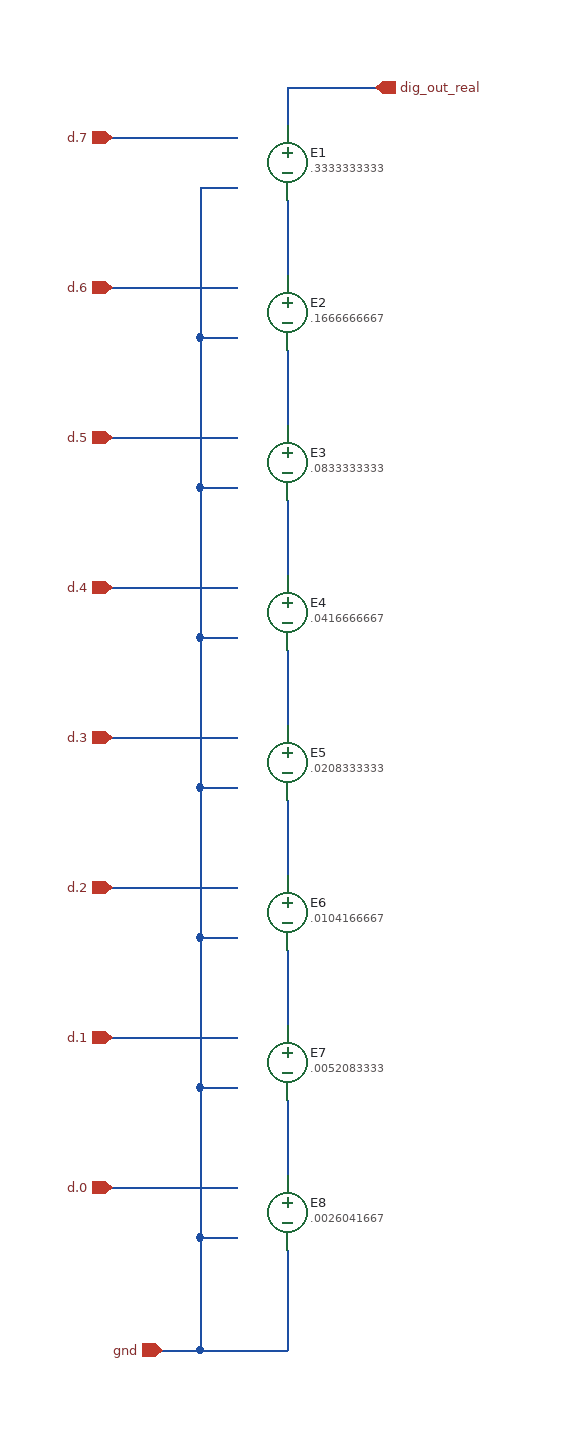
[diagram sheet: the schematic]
v {xschem version=3.4.6RC file_version=1.2
}
G {}
K {}
V {}
S {}
E {}
N 490 -1100 490 -1070 {lab=dig_out_real}
N 490 -1100 560 -1100 {lab=dig_out_real}
N 490 -1010 490 -980 {lab=#net1}
N 380 -1060 450 -1060 {lab=d.0}
N 420 -1020 450 -1020 {lab=gnd}
N 420 -1020 420 -990 {lab=gnd}
N 350 -1060 380 -1060 {lab=d.0}
N 490 -980 490 -950 {lab=#net1}
N 490 -890 490 -860 {lab=#net2}
N 380 -940 450 -940 {lab=d.6}
N 420 -900 450 -900 {lab=gnd}
N 420 -900 420 -870 {lab=gnd}
N 350 -940 380 -940 {lab=d.6}
N 490 -860 490 -830 {lab=#net2}
N 490 -770 490 -740 {lab=#net3}
N 380 -820 450 -820 {lab=d.5}
N 420 -780 450 -780 {lab=gnd}
N 420 -780 420 -750 {lab=gnd}
N 350 -820 380 -820 {lab=d.5}
N 490 -740 490 -710 {lab=#net3}
N 490 -650 490 -620 {lab=#net4}
N 380 -700 450 -700 {lab=d.4}
N 420 -660 450 -660 {lab=gnd}
N 420 -660 420 -630 {lab=gnd}
N 350 -700 380 -700 {lab=d.4}
N 490 -620 490 -590 {lab=#net4}
N 490 -530 490 -500 {lab=#net5}
N 380 -580 450 -580 {lab=d.3}
N 420 -540 450 -540 {lab=gnd}
N 420 -540 420 -510 {lab=gnd}
N 350 -580 380 -580 {lab=d.3}
N 490 -500 490 -470 {lab=#net5}
N 490 -410 490 -380 {lab=#net6}
N 380 -460 450 -460 {lab=d.2}
N 420 -420 450 -420 {lab=gnd}
N 420 -420 420 -390 {lab=gnd}
N 350 -460 380 -460 {lab=d.2}
N 490 -380 490 -350 {lab=#net6}
N 490 -290 490 -260 {lab=#net7}
N 380 -340 450 -340 {lab=d.1}
N 420 -300 450 -300 {lab=gnd}
N 420 -300 420 -270 {lab=gnd}
N 350 -340 380 -340 {lab=d.1}
N 490 -260 490 -230 {lab=#net7}
N 490 -170 490 -140 {lab=gnd}
N 380 -220 450 -220 {lab=d.0}
N 420 -180 450 -180 {lab=gnd}
N 420 -180 420 -150 {lab=gnd}
N 350 -220 380 -220 {lab=d.0}
N 490 -140 490 -120 {lab=gnd}
N 420 -150 420 -90 {lab=gnd}
N 390 -90 420 -90 {lab=gnd}
N 420 -90 490 -90 {lab=gnd}
N 490 -120 490 -90 {lab=gnd}
N 420 -270 420 -180 {lab=gnd}
N 420 -390 420 -300 {lab=gnd}
N 420 -510 420 -420 {lab=gnd}
N 420 -630 420 -540 {lab=gnd}
N 420 -750 420 -660 {lab=gnd}
N 420 -870 420 -780 {lab=gnd}
N 420 -990 420 -900 {lab=gnd}
C {vcvs.sym} 490 -1040 0 0 {name=E1 value=.3333333333}
C {vcvs.sym} 490 -920 0 0 {name=E2 value=.1666666667}
C {vcvs.sym} 490 -800 0 0 {name=E3 value=.0833333333}
C {vcvs.sym} 490 -680 0 0 {name=E4 value=.0416666667}
C {vcvs.sym} 490 -560 0 0 {name=E5 value=.0208333333}
C {vcvs.sym} 490 -440 0 0 {name=E6 value=.0104166667}
C {vcvs.sym} 490 -320 0 0 {name=E7 value=.0052083333}
C {vcvs.sym} 490 -200 0 0 {name=E8 value=.0026041667}
C {iopin.sym} 390 -90 2 0 {name=p1 lab=gnd}
C {ipin.sym} 350 -220 0 0 {name=p12 lab=d.0}
C {ipin.sym} 350 -340 0 0 {name=p2 lab=d.1}
C {ipin.sym} 350 -460 0 0 {name=p3 lab=d.2}
C {ipin.sym} 350 -580 0 0 {name=p4 lab=d.3}
C {ipin.sym} 350 -700 0 0 {name=p5 lab=d.4}
C {ipin.sym} 350 -820 0 0 {name=p6 lab=d.5}
C {ipin.sym} 350 -940 0 0 {name=p7 lab=d.6}
C {ipin.sym} 350 -1060 0 0 {name=p8 lab=d.7}
C {opin.sym} 560 -1100 0 0 {name=p21 lab=dig_out_real}
